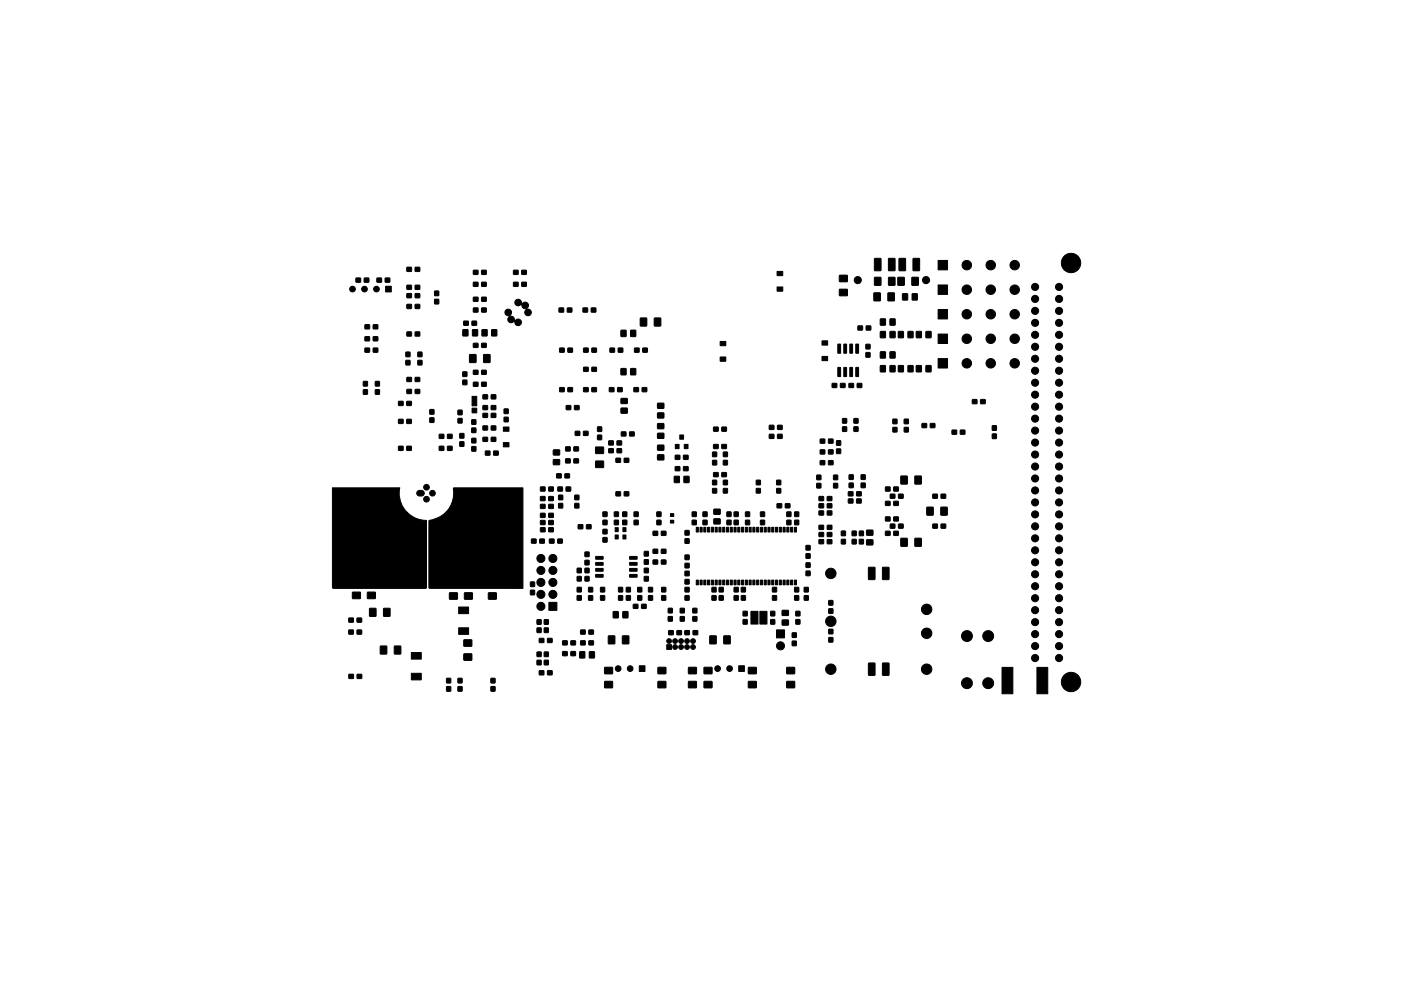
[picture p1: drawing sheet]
<svg xmlns="http://www.w3.org/2000/svg" width="297mm" height="210mm" viewBox="0 0 297 210" stroke-linecap="round" stroke-linejoin="round" font-family="sans-serif">
<g fill="#000" stroke="#000" stroke-width=".21">
<path d="M75.5 59h.9v.9h-.9zM77.2 59h1v.9h-1zM79.9 59h1v.9h-1zM81.7 59h.9v.9h-.9zM86.3 56.7h.9v.9h-.9zM88 56.7h1v.9h-1zM100.4 59.9h.9v.8h-.9zM100.4 57.4h.9v.8h-.9zM102.1 59.9h1v.8h-1zM102.1 57.4h1v.8h-1zM108.9 59.9h.9v.8h-.9zM108.9 57.4h.9v.8h-.9z"/>
<path d="M110.6 59.9h1v.8h-1zM110.6 57.4h1v.8h-1zM164.8 57.6h1.2v.9h-1.2zM178 58.4h1.6l.1 1.3-1.7 .1zM185.4 58.9h1.4l-.1 1.6h-1.3zM185.4 54.9h1.4l-.1 2.5-1.3-.1zM188.4 58.9h1.3v1.6h-1.3zM188.4 54.9h1.4l-.1 2.5-1.3-.1zM190.4 58.9h1.3v1.6h-1.3zM190.6 54.9h1.4l-.1 2.5-1.3-.1zM193.4 58.9h1.3v1.6h-1.4zM193.6 54.9h1.4l-.1 2.5-1.3-.1z"/>
<path d="M198.9 55.3h2v2h-2zM77.4 73.9h.9v.8h-.9zM77.4 71.5h.9v.8h-.9zM77.4 68.9h.9v.9h-.9zM79.1 73.9h1v.8h-1zM79.1 71.5h1v.8h-1zM79.1 68.9h1v.9h-1zM81.8 60.7h1.2v1.2h-1.2zM86.1 76.5h.8v.9h-.8zM86.1 74.7h.8v1h-.8zM86.3 70.4h.9v.9h-.9zM86.3 64.6h.9v.8h-.9z"/>
<path d="M86.3 62.3h.9v.9h-.9zM86.3 60.5h.9v.9h-.9zM88 70.4h1v.9h-1zM88 64.6h1v.8h-1zM88 62.3h1v.9h-1zM88 60.5h1v.9h-1zM88.6 76.5h.9v.9h-.9zM88.6 74.7h.9v1h-.9zM92.2 63.5h.8v1h-.8zM92.2 61.8h.8v.9h-.8zM98.1 78.9h.9v1h-.9zM98.1 70h1.1v1.3l-1.1-.1z"/>
<path d="M98.3 68.2h1v.8h-1zM99.6 75.2l1.3 .1v1.6h-1.3zM100.1 68.2h.9v.8h-.9zM100.2 70h1.1l-.1 1.3-1-.1zM100.4 78.6h.9v.8h-.9zM100.4 72.8h.9v.9h-.9zM100.4 65.4h.9v.8h-.9zM100.4 63.1h.9v.8h-.9zM102.1 78.6h1v.8h-1zM102.1 72.8h1v.9h-1zM102.1 65.4h1v.8h-1zM102.1 63.1h1v.8h-1z"/>
<path d="M102.2 70h1.1l-.1 1.3-1-.1zM102.6 75.2l1.3 .1v1.6h-1.4zM104.3 70h1v1.3l-1.1-.1zM107.3 65.7a.75 .75 0 0 1 1.1 .3 .75 .75 0 0 1-.3 1 .94 .94 0 0 1 1.1 1 .7 .7 0 0 1 1-.2 .7 .7 0 0 1 .1 1.1 .7 .7 0 0 1-1.1-.3l-.1-.5a.78 .78 0 0 1-1.2 .2 .78 .78 0 0 1 .1-1.2v-.1a.77 .77 0 0 1-.8-.4 .77 .77 0 0 1 .1-.9zM109.3 63.7a.81 .81 0 0 1 .9-.1 .81 .81 0 0 1 .4 .8l.1 .1a.77 .77 0 0 1 1.2-.2 .77 .77 0 0 1-.2 1.2 .71 .71 0 0 1 1 .6 .71 .71 0 0 1-.7 .8 .71 .71 0 0 1-.7-.8l.3-.6a.94 .94 0 0 1-1-1 .74 .74 0 0 1-1.1 .3 .74 .74 0 0 1-.2-1.1zM118.5 65.4h1v.8h-1zM118.7 73.9h.9v.8h-.9zM120.3 65.4h.9v.8h-.9zM120.4 73.9h1v.8h-1zM123.6 65.4h1v.8h-1zM123.7 77.9h1v.9h-1zM123.7 73.9h1v.8h-1z"/>
<path d="M125.4 65.4h.9v.8h-.9zM125.5 77.9h.9v.9h-.9zM125.5 73.9h.9v.8h-.9zM129.3 73.9h1v.8h-1zM131.1 73.9h.9v.8h-.9zM131.7 78.2h1v1.3h-1zM131.7 70.1h1v1.3h-1zM133.7 78.2h1.1l-.1 1.3h-1zM133.7 70.1h1.1l-.1 1.3h-1zM134.5 73.9h1v.8h-1zM135.8 67.5h1.3v1.7l-1.3-.1zM136.3 73.9h.9v.8h-.9z"/>
<path d="M138.7 67.5h1.4l-.1 1.7-1.3-.1zM152.7 75.7h1.2v.9h-1.2zM152.7 72.4h1.2v.9h-1.2zM164.8 60.9h1.2v.9h-1.2zM174.3 75.6h1.2v.9h-1.2zM174.3 72.3h1.2v.9h-1.2zM177.7 78h.5v1.9l-.6-.1zM177.7 73l.5 .1v1.8h-.6zM178.9 78h.6l-.1 1.9-.5-.1zM178.9 73l.6 .1-.1 1.8h-.5zM178 61.4h1.6l.1 1.3h-1.7zM180.2 78h.6l-.1 1.9-.5-.1z"/>
<path d="M180.2 73l.6 .1-.1 1.8h-.5zM181.5 78h.5v1.9l-.6-.1zM181.5 73l.5 .1v1.8h-.6zM181.9 69.2h1v.8h-1zM183.6 74.8h.8v1h-.8zM183.6 73.1h.8v.9h-.8zM183.7 69.2h.9v.8h-.9zM185.3 62.2h1.3v1.6h-1.3zM186.7 77.6h1v1.3l-1.1-.1zM186.7 74.7h1v1.3l-1.1-.1zM186.7 70.3l1 .1v1.3l-1.1-.1zM186.7 67.7h1v1.3l-1.1-.1z"/>
<path d="M188.3 62.2h1.3v1.6h-1.3zM188.7 77.6h1.1l-.1 1.3-1-.1zM188.7 74.7h1.1l-.1 1.3-1-.1zM188.7 70.3l1.1 .1-.1 1.3-1-.1zM188.7 67.7h1.1l-.1 1.3-1-.1zM190.5 77.6h1v1.3l-1-.1zM190.5 70.3l1 .1v1.3l-1-.1zM191.4 62.3l1 .1v1.3l-1.1-.1zM192.5 77.6h1.1l-.1 1.3-1-.1zM192.5 70.3l1.1 .1-.1 1.3-1-.1zM193.4 62.3l1.1 .1-.1 1.3-1-.1zM194.3 77.6h1.1l-.1 1.3-1-.1z"/>
<path d="M194.3 70.3l1.1 .1-.1 1.3-1-.1zM196.3 77.6h1.1v1.3l-1.1-.1zM196.3 70.3l1.1 .1v1.3l-1.1-.1zM198.9 76.1h2v2h-2zM198.9 70.9h2v2h-2zM198.9 65.7h2v2h-2zM198.9 60.5h2v2h-2zM77 82.7h.9v.9h-.9zM77 80.9h.9v1h-.9zM79.6 82.7h.8v.9h-.8zM79.6 80.9h.8v1h-.8zM84.5 94.7h1v.8h-1z"/>
<path d="M84.5 89h1v.8h-1zM84.5 85.2h1v.8h-1zM86.3 94.7h.9v.8h-.9zM86.3 89h.9v.8h-.9zM86.3 85.2h.9v.8h-.9zM86.3 82.6h.9v.9h-.9zM86.3 80.1h.9v.8h-.9zM88 82.6h1v.9h-1zM88 80.1h1v.8h-1zM91.1 88.7h.9v.9h-.9zM91.1 86.9h.9v1h-.9zM93.1 94.7h1v.8h-1z"/>
<path d="M93.1 92.2h1v.8h-1zM94.9 94.7h.9v.8h-.9zM94.9 92.2h.9v.8h-.9zM97.1 88.8h.9v.9h-.9zM97.1 87h.9v1h-.9zM97.5 93.7h.8v1h-.8zM97.5 92h.8v.9h-.8zM98.1 80.7h.9v.9h-.9zM100 94.8h.9v.9h-.9zM100 93h.9v1h-.9zM100 90.8h.9v1h-.9zM100 89.1h.9v.9h-.9z"/>
<path d="M100.1 86.6h1v1h-1zM100.1 84.1h1v2h-1zM100.4 81.1h.9v.9h-.9zM102.1 81.1h1v.9h-1zM102.4 92.8h1v.8h-1zM102.4 90.4h1v.8h-1zM102.4 87.7h1v.9h-1zM102.4 86.1h1v.8h-1zM102.4 83.8h1v.8h-1zM102.9 95.7h1v.9h-1zM104.2 92.8h.9v.8h-.9zM104.2 90.4h.9v.8h-.9z"/>
<path d="M104.2 87.7h.9v.9h-.9zM104.2 86.1h.9v.8h-.9zM104.2 83.8h.9v.8h-.9zM104.7 95.7h.9v.9h-.9zM106.9 88.5h.8v1h-.8zM106.9 86.8h.8v.9h-.8zM106.7 93.9h1.2v.9h-1.2zM106.7 90.6h1.2v.9h-1.2zM117.3 97.5h1.3l.1 1-1.3 .1zM117.3 95.5h1.3l.1 1h-1.3zM118.7 82.2h.9v.9h-.9zM119.9 97.4h1v.8h-1z"/>
<path d="M119.9 94.8h1v.9h-1zM120.1 86.1h.9v.8h-.9zM120.4 82.2h1v.9h-1zM121.7 97.4h.9v.8h-.9zM121.7 94.8h.9v.9h-.9zM121.8 86.1h1v.8h-1zM122 91.5h.9v.9h-.9zM123.7 91.5h1v.9h-1zM123.7 82.2h1v.9h-1zM125.5 82.2h.9v.9h-.9zM126.7 92.3h.9v1h-.9zM126.7 90.6h.9v.9h-.9z"/>
<path d="M126.3 97.8h1.6l.1 1.3-1.7 .1zM126.3 94.9h1.6l.1 1.3h-1.7zM129.1 95.2h.9v.8h-.9zM129.1 93.6h.9v.8h-.9zM129.2 82.2h1v.9h-1zM130.6 97.2h1v.9h-1zM130.8 95.2h1v.8h-1zM130.8 93.6h1v.8h-1zM131 82.2h.9v.9h-.9zM131.7 91.6h1v.9h-1zM131.7 86.6h1.3v1l-1.3 .1zM131.7 84.6l1.3-.1v1.1h-1.3z"/>
<path d="M132.4 97.2h.9v.9h-.9zM133.5 91.6h.9v.9h-.9zM134.4 82.2h1v.9h-1zM136.2 82.2h.9v.9h-.9zM139.4 96.5h1.3l.1 1-1.3 .1zM139.4 94.5l1.3-.1 .1 1.1h-1.3zM139.4 91.9h1.3l.1 1.1h-1.3zM139.4 89.9h1.3l.1 1-1.3 .1zM139.4 87.6h1.3l.1 1-1.3 .1zM139.4 85.6l1.3-.1 .1 1.1h-1.3zM143.2 94.3h.8v.9h-.8zM143.2 99h.9v.9h-.9z"/>
<path d="M143.2 96.6h.9v.8h-.9zM144.1 92.3h.8v.9h-.8zM144.9 99h1v.9h-1zM144.9 96.6h1v.8h-1zM145.1 94.3h.8v.9h-.8zM151.1 97.7h.8v.9h-.8zM151.1 95.9h.8v1h-.8zM151.3 94.3h1v.9h-1zM151.3 90.6h1v.9h-1zM153.1 94.3h.9v.9h-.9zM153.1 90.6h.9v.9h-.9zM153.4 97.7h.8v.9h-.8z"/>
<path d="M153.4 95.9h.8v1h-.8zM163.1 92.2h1v.8h-1zM163.1 90.2h1v.9h-1zM164.9 92.2h.9v.8h-.9zM164.9 90.2h.9v.9h-.9zM173.9 97.7h1v.9h-1zM173.9 95.5h1v.8h-1zM173.9 93.2h1v.8h-1zM175.7 97.7h.9v.9h-.9zM175.7 95.5h.9v.8h-.9zM175.7 93.2h.9v.8h-.9zM176.5 81.4h.9v.8h-.9z"/>
<path d="M177.4 95.3h.8v.9h-.8zM177.4 93.5h.8v1h-.8zM178.2 81.4h.9v.8h-.9zM178.6 90.6h.9v.9h-.9zM178.6 88.8h.9v1h-.9zM180 81.4h1v.8h-1zM181.1 90.6h.8v.9h-.8zM181.1 88.8h.8v1h-.8zM181.8 81.4h.9v.8h-.9zM189.3 90.7h.9v.9h-.9zM189.3 88.9h.9v1h-.9zM191.7 90.7h.9v.9h-.9z"/>
<path d="M191.7 88.9h.9v1h-.9zM195.5 89.9h.9v.8h-.9zM197.3 89.9h.9v.8h-.9zM201.9 91.3h.9v.8h-.9zM203.6 91.3h1v.8h-1zM206.2 84.8h.9v.8h-.9zM207.9 84.8h1v.8h-1zM210.4 92.1h.8v.9h-.8zM210.4 90.3h.8v1h-.8zM70.5 103.5h14.3l-.2 1.6 .3 1.3 .4 .9 .6 1 1.1 1a5.4 5.4 0 0 0 2.7 1.1h.7v14.3l-.1 .1h-19.7l-.1-.1zM88.5 104.2l.9-.2a.6 .6 0 0 1 .6 .6 .6 .6 0 0 1-.6 .6h-.5a.6 .6 0 0 1-.5-.3 .6 .6 0 0 1 .1-.7zM112.7 114.4h.9v.8h-.9z"/>
<path d="M114.4 114.4h1v.8h-1zM114.6 112h.9v.8h-.9zM114.6 110.4h.9v.9h-.9zM114.6 108.9h.9v.9h-.9zM114.6 107h.9v.9h-.9zM114.6 105.4h.9v.8h-.9zM114.6 103.3h.9v.9h-.9zM116.4 112h.9v.8h-.9zM116.4 110.4h.9v.9h-.9zM116.4 108.9h.9v.9h-.9zM116.4 107h.9v.9h-.9zM116.4 105.4h.9v.8h-.9z"/>
<path d="M116.4 103.3h.9v.9h-.9zM116.5 114.4h1v.8h-1zM118 100.5h1v.9h-1zM118.3 114.4h.9v.8h-.9zM118.3 103.3h.9v.9h-.9zM118.4 106.8h.9v1h-.9zM118.4 105.1h.9v.9h-.9zM119.8 100.5h.9v.9h-.9zM120 103.3h1v.9h-1zM121.9 106.8h.8v1h-.8zM121.9 105.1h.8v.9h-.8zM122.6 111.3h1v.9h-1z"/>
<path d="M124 118.9h.9v.9h-.9zM124 117.1h.9v1h-.9zM124.4 111.3h.9v.9h-.9zM126.3 119.4l1.5-.1 .1 .6h-1.6zM126.3 118.1h1.5l.1 .5-1.6 .1zM127.8 114.1h.9v.9h-.9zM127.8 112.3h.9v1h-.9zM127.8 110.4h.9v.9h-.9zM127.8 108.6h.9v1h-.9zM130.3 110.4h.8v.9h-.8zM130.3 108.6h.8v1h-.8zM130.4 113.5h.7v.9h-.7z"/>
<path d="M130.4 112h.7v.8h-.7zM130.6 104.3h1v.9h-1zM132.1 113.5h.6v.9h-.6zM132.1 112h.6v.8h-.6zM132 110.4h.9v.9h-.9zM132 108.6h.9v1h-.9zM132.4 104.3h.9v.9h-.9zM133.5 119.4l1.5-.1 .1 .6h-1.6zM133.5 118.1h1.5l.1 .5-1.6 .1zM134.5 110.4h.8v.9h-.8zM134.5 108.6h.8v1h-.8zM136.6 118.8h.9v.9h-.9z"/>
<path d="M136.6 117h.9v1h-.9zM138.5 118.8h.9v.9h-.9zM138.5 116.5h.9v.9h-.9zM138.5 112.7h.9v.9h-.9zM139.3 110.4h.8v.9h-.8zM139.3 108.6h.8v1h-.8zM140.2 118.8h1v.9h-1zM140.2 116.5h1v.9h-1zM140.2 112.7h1v.9h-1zM142.1 110.4h.7v.6h-.7zM142.1 109h.7v.6h-.7zM143 101.1h1v1.3l-1-.1z"/>
<path d="M145 101.1h1.1l-.1 1.3-1-.1zM145.2 119.5h.9v1h-.9zM145.2 117.8h.9v.9h-.9zM145.2 114.3h.9v1h-.9zM145.2 112.6h.9v.9h-.9zM146.8 110.4h.8v.9h-.8zM146.8 108.6h.8v1h-.8zM147.6 111.9h.5v1h-.5zM148.4 111.9h.5v1h-.5zM149.2 111.9h.5v1h-.5zM149.1 110.4h.8v.9h-.8zM149.1 108.6h.8v1h-.8z"/>
<path d="M150 111.9h.5v1h-.5zM150.8 111.9h.5v1h-.5zM151.1 103.6h.8v1h-.8zM151.1 101.9h.8v.9h-.8zM151.6 111.9h.5v1h-.5zM151.3 100.3h1v.8h-1zM151.4 110.1h1.2l.1 1-1.3 .1zM151.4 108h1.2l.1 1.1h-1.3zM152.4 111.9h.5v1h-.5zM153.2 111.9h.5v1h-.5zM153.1 100.3h.9v.8h-.9zM153.4 103.6h.8v1h-.8z"/>
<path d="M153.4 101.9h.8v.9h-.8zM154 111.9h.5v1h-.5zM154.1 110.4h.9v.9h-.9zM154.1 108.6h.9v1h-.9zM154.8 111.9h.5v1h-.5zM155.6 111.9h.5v1h-.5zM155.7 110.4h.8v.9h-.8zM155.7 108.6h.8v1h-.8zM156.4 111.9h.5v1h-.5zM157.2 111.9h.5v1h-.5zM158 111.9h.5v1h-.5zM158.1 110.4h.8v.9h-.8z"/>
<path d="M158.1 108.6h.8v1h-.8zM158.8 111.9h.5v1h-.5zM159.6 111.9h.5v1h-.5zM160.4 111.9h.5v1h-.5zM160.4 103.6h.8v1h-.8zM160.4 101.9h.8v.9h-.8zM161.2 111.9h.5v1h-.5zM161.2 110.4h.9v.9h-.9zM161.2 108.6h.9v1h-.9zM162 111.9h.5v1h-.5zM162.8 111.9h.5v1h-.5zM163.6 111.9h.5v1h-.5z"/>
<path d="M164.4 111.9h.5v1h-.5zM164.7 103.6h.8v1h-.8zM164.7 101.9h.8v.9h-.8zM164.8 106.9h.9v.8h-.9zM165.2 111.9h.5v1h-.5zM166 111.9h.5v1h-.5zM166.8 111.9h.5v1h-.5zM166.5 106.9h1v.8h-1zM166.8 110.4h.9v.9h-.9zM166.8 108.6h.9v1h-.9zM167.6 111.9h.5v1h-.5zM168.4 111.9h.5v1h-.5z"/>
<path d="M168.5 110.4h.8v.9h-.8zM168.5 108.6h.8v1h-.8zM170.9 119.4h.8v1h-.8zM170.9 117.5h.8v.9h-.8zM170.9 115.7h.8v1h-.8zM173.2 102.6h.8v.9h-.8zM173.2 100.8h.8v1h-.8zM173.7 114.5h.9v.9h-.9zM173.7 113h.9v.8h-.9zM173.7 111.5h.9v.8h-.9zM173.7 108.4h.9v.9h-.9zM173.7 106.9h.9v.8h-.9z"/>
<path d="M173.7 105.4h.9v.8h-.9zM175.4 114.5h1v.9h-1zM175.4 113h1v.8h-1zM175.4 111.5h1v.8h-1zM175.4 108.4h1v.9h-1zM175.4 106.9h1v.8h-1zM175.4 105.4h1v.8h-1zM176.7 102.6h.9v.9h-.9zM176.7 100.8h.9v1h-.9zM178.4 114.4h.8v1h-.8zM178.4 112.7h.8v.9h-.8zM179.9 105.9h.9v.8h-.9z"/>
<path d="M179.9 104.3h.9v.9h-.9zM180 102.5h.9v1h-.9zM180 100.8h.9v.9h-.9zM180.7 114.4h.8v1h-.8zM180.7 112.7h.8v.9h-.8zM181.6 105.9h1v.8h-1zM181.6 104.3h1v.9h-1zM182.2 114.4h.8v1h-.8zM182.2 112.7h.8v.9h-.8zM182.6 102.5h.8v1h-.8zM182.6 100.8h.8v.9h-.8zM183.8 114.5h1.2l.1 1.1h-1.3z"/>
<path d="M183.8 112.5h1.2l.1 1-1.3 .1zM187.8 112.7h.9v.9h-.9zM187.8 109.7h.9v.8h-.9zM187.8 106.4h.9v.8h-.9zM187.8 103.3h.9v.9h-.9zM188.8 111.2h.9v.9h-.9zM188.8 104.9h.9v.8h-.9zM189.5 112.7h1v.9h-1zM189.5 109.7h1v.8h-1zM189.5 106.4h1v.8h-1zM189.5 103.3h1v.9h-1zM190.5 111.2h1v.9h-1z"/>
<path d="M190.5 104.9h1v.8h-1zM191 114.2l1.4 .1-.1 1.6h-1.3zM191 101h1.4l-.1 1.7-1.3-.1zM194 114.2l1.3 .1v1.6h-1.3zM194 101h1.3v1.7l-1.3-.1zM196.5 107.6l1.4 .1-.1 1.6h-1.3zM197.8 111.2h.9v.9h-.9zM197.8 104.9h.9v.8h-.9zM199.5 111.2h1v.9h-1zM199.5 104.9h1v.8h-1zM199.5 107.6l1.3 .1v1.6h-1.3zM74 133.7h.9v.8h-.9z"/>
<path d="M74 131.1h.9v.9h-.9zM74.7 125.7l1.7-.1v1.4h-1.6zM75.7 133.7h1v.8h-1zM75.7 131.1h1v.9h-1zM77.9 125.7l1.6-.1 .1 1.4h-1.7zM78.4 129.1h1.3v1.7l-1.4-.1zM80.7 137.1h1.3v1.7l-1.4-.1zM81.3 129.1h1.4l-.1 1.7-1.3-.1zM83.6 137.1h1.4l-.1 1.7-1.3-.1zM87.2 138.4h2.1v1.4h-2.1zM95.3 125.8h1.6l.1 1.3h-1.7zM97.2 133.2h2.1v1.4h-2.1z"/>
<path d="M97.2 128.8h2.1v1.4h-2.1zM98.4 138.7h1.6v1.3l-1.6 .1zM98.4 135.8l1.6-.1v1.4h-1.6zM98.5 125.8h1.6l.1 1.3h-1.7zM103.6 125.8h1.6v1.3h-1.6zM96.2 103.5h14.7v21.3h-19.8l-.2-.1v-14.2l.9-.3a6.1 6.1 0 0 0 3.1-1.9l.7-1.2 .4-1.1zM112.5 125.2h.8v1h-.8zM112.5 123.5h.8v.9h-.8zM113.9 138.3h.8v1h-.8zM113.9 133.2h.8v1h-.8zM113.9 131.5h.8v.9h-.8zM114.3 135.5h1v.8h-1z"/>
<path d="M115.4 138.3h.8v1h-.8zM115.4 133.2h.8v1h-.8zM115.4 131.5h.8v.9h-.8zM116.1 135.5h.9v.8h-.9zM116.4 127.8h1.7v1.7h-1.7zM119.3 138.3h.9v.8h-.9zM119.3 136h.9v.8h-.9zM121.1 138.3h.9v.8h-.9zM121.1 136h.9v.8h-.9zM122.4 126.4h.8v.9h-.8zM122.4 124.6h.8v1h-.8zM122.4 122.3h.8v1h-.8z"/>
<path d="M122.4 120.6h.8v.9h-.8zM122.9 138.3h1.1l-.1 1.3h-1zM123.1 136h1v.8h-1zM123.1 133.7h1v.8h-1zM124 122.3h.9v1h-.9zM124 120.6h.9v.9h-.9zM124.8 126.4h.8v.9h-.8zM124.8 124.6h.8v1h-.8zM124.9 136h.9v.8h-.9zM124.9 133.7h.9v.8h-.9zM125 138.3h1v1.3h-1.1zM126.3 121.9h1.5l.1 .5-1.6 .1z"/>
<path d="M126.3 120.6h1.5l.1 .5-1.6 .1zM127.3 126.4h.9v.9h-.9zM127.3 124.6h.9v1h-.9zM129 134.9l1.4 .1-.1 1.6h-1.3zM130 129.8h1.1l-.1 1.3-1-.1zM131.1 126.4h.9v.9h-.9zM131.1 124.6h.9v1h-.9zM132.1 129.8h1v1.3l-1-.1zM132 134.9l1.3 .1v1.6h-1.3zM132.8 126.4h.8v.9h-.8zM132.8 124.6h.8v1h-.8zM133.5 121.9h1.5l.1 .5-1.6 .1z"/>
<path d="M133.5 120.6h1.5l.1 .5-1.6 .1zM134.3 128.2h.9v.9h-.9zM135.2 126.4h.9v.9h-.9zM135.2 124.6h.9v1h-.9zM136 128.2h1v.9h-1zM136.6 122.3h.9v1h-.9zM136.6 120.6h.9v.9h-.9zM137.5 126.4h.8v.9h-.8zM137.5 124.6h.8v1h-.8zM140.3 126.4h.8v.9h-.8zM140.3 124.6h.8v1h-.8zM141.4 136.8h1v1h-1z"/>
<path d="M141.7 130.8h.8v1h-.8zM141.7 129.1h.8v.9h-.8zM141.8 133.8h.9v.9h-.9zM143.5 133.8h1v.9h-1zM144.2 130.8h.9v1h-.9zM144.2 129.1h.9v.9h-.9zM145.2 126.4h.9v.9h-.9zM145.2 124.6h.9v1h-.9zM145.2 123h.9v.9h-.9zM145.2 121.2h.9v.9h-.9zM145.2 133.8h1v.9h-1zM146.9 130.8h.8v1h-.8z"/>
<path d="M146.9 129.1h.8v.9h-.8zM147 133.8h.9v.9h-.9zM147.6 123.1h.5v1h-.5zM148.4 123.1h.5v1h-.5zM149.2 123.1h.5v1h-.5zM150 123.1h.5v1h-.5zM150.8 123.1h.5v1h-.5zM151 126.4h.8v.9h-.8zM151 124.6h.8v1h-.8zM150.5 134.9l1.4 .1-.1 1.6h-1.3zM151.6 123.1h.5v1h-.5zM152.4 123.1h.5v1h-.5z"/>
<path d="M152.5 126.4h.8v.9h-.8zM152.5 124.6h.8v1h-.8zM153.2 123.1h.5v1h-.5zM154 123.1h.5v1h-.5zM153.5 134.9l1.3 .1v1.6h-1.3zM154.8 123.1h.5v1h-.5zM155.6 123.1h.5v1h-.5zM155.7 126.4h.8v.9h-.8zM155.7 124.6h.8v1h-.8zM156.4 123.1h.5v1h-.5zM157.2 123.1h.5v1h-.5zM157.2 126.4h.8v.9h-.8z"/>
<path d="M157.2 124.6h.8v1h-.8zM157.6 131.5h.8v.9h-.8zM157.6 129.7h.8v1h-.8zM158 123.1h.5v1h-.5zM158.8 123.1h.5v1h-.5zM159.6 123.1h.5v1h-.5zM159.2 129.7h1.5v2.7h-1.5zM160.4 123.1h.5v1h-.5zM161.2 123.1h.5v1h-.5zM162 123.1h.5v1h-.5zM161.1 129.7h1.5v2.7h-1.5zM162.8 123.1h.5v1h-.5z"/>
<path d="M163.6 123.1h.5v1h-.5zM163.4 131.5h.9v.9h-.9zM163.4 129.7h.9v1h-.9zM163.8 126.4h.8v.9h-.8zM163.8 124.6h.8v1h-.8zM164.4 123.1h.5v1h-.5zM165.2 123.1h.5v1h-.5zM164.6 133.6h1.7v1.7h-1.7zM166 123.1h.5v1h-.5zM165.9 131.6l1.2-.1 .1 1.1h-1.3zM165.9 129.5h1.2l.1 1-1.3 .1zM166.8 123.1h.5v1h-.5z"/>
<path d="M167.6 123.1h.5v1h-.5zM168 136h.8v1h-.8zM168 134.3h.8v.9h-.8zM168.4 123.1h.5v1h-.5zM168.5 126.4h.8v.9h-.8zM168.5 124.6h.8v1h-.8zM168.7 131.5h.9v.9h-.9zM168.7 129.7h.9v1h-.9zM170.5 126.4h.9v.9h-.9zM170.5 124.6h.9v1h-.9zM170.9 121.2h.8v.9h-.8zM175.7 135.3h.9v.9h-.9z"/>
<path d="M175.7 133.5h.9v1h-.9zM175.7 129.2h.9v.9h-.9zM175.7 127.4h.9v1h-.9zM184.2 120.4h1.3l-.1 2.6-1.3-.1zM187.1 120.4h1.4l-.1 2.6-1.3-.1zM74 143.1h.9v.8h-.9zM75.7 143.1h1v.8h-1zM87.2 142.8h2.1v1.4h-2.1zM94.7 145.7h.8v.9h-.8zM94.7 143.9h.8v1h-.8zM97.1 145.7h.9v.9h-.9zM97.1 143.9h.9v1h-.9z"/>
<path d="M104.1 145.7h.8v.9h-.8zM104.1 143.9h.8v1h-.8zM113.9 140.1h.8v.9h-.8zM114.3 142.3h1v.9h-1zM115.4 140.1h.8v.9h-.8zM116.1 142.3h.9v.9h-.9zM128.2 144.6h1.6l.1 1.3h-1.7zM128.2 141.6h1.6l.1 1.3-1.7 .1zM135.5 141.3h1.2v1.2h-1.2zM139.5 144.6h1.6l.1 1.3h-1.7zM139.5 141.6h1.6l.1 1.3-1.7 .1zM146 144.6h1.6l.1 1.3h-1.7z"/>
<path d="M146 141.6h1.6l.1 1.3-1.7 .1zM149.3 144.6h1.6l.1 1.3h-1.7zM149.3 141.6h1.6l.1 1.3-1.7 .1zM156.6 141.3h1.2v1.2h-1.2zM158.7 144.6h1.6l.1 1.3h-1.7zM158.7 141.6h1.6l.1 1.3-1.7 .1zM166.8 144.6h1.6l.1 1.3h-1.7zM166.8 141.6h1.6l.1 1.3-1.7 .1zM184.2 140.7l1.3 .1-.1 2.5-1.3-.1zM187.1 140.7l1.4 .1-.1 2.5-1.3-.1zM212.4 141.6h2.3v5.6h-2.3zM219.8 141.6h2.3v5.6h-2.3z"/>
<circle cx="181.9" cy="59.4" r=".75"/>
<circle cx="196.3" cy="59.4" r=".75"/>
<circle cx="205" cy="56.3" r="1"/>
<circle cx="210.1" cy="56.3" r="1"/>
<circle cx="215.1" cy="56.3" r="1"/>
<circle cx="227.1" cy="55.8" r="2.06"/>
<circle cx="74.7" cy="61.3" r=".6"/>
<circle cx="77.3" cy="61.3" r=".6"/>
<circle cx="79.8" cy="61.3" r=".6"/>
<circle cx="205" cy="66.7" r="1"/>
<circle cx="205" cy="61.5" r="1"/>
<circle cx="205" cy="71.9" r="1"/>
<circle cx="205" cy="77.1" r="1"/>
<circle cx="210.1" cy="66.7" r="1"/>
<circle cx="210.1" cy="61.5" r="1"/>
<circle cx="210.1" cy="77.1" r="1"/>
<circle cx="210.1" cy="71.9" r="1"/>
<circle cx="215.1" cy="66.7" r="1"/>
<circle cx="215.1" cy="61.5" r="1"/>
<circle cx="215.1" cy="71.9" r="1"/>
<circle cx="215.1" cy="77.1" r="1"/>
<circle cx="219.5" cy="78.7" r=".75"/>
<circle cx="219.5" cy="63.4" r=".75"/>
<circle cx="219.5" cy="73.6" r=".75"/>
<circle cx="219.5" cy="68.5" r=".75"/>
<circle cx="219.5" cy="66" r=".75"/>
<circle cx="219.5" cy="71" r=".75"/>
<circle cx="219.5" cy="60.9" r=".75"/>
<circle cx="219.5" cy="76.1" r=".75"/>
<circle cx="224.5" cy="78.7" r=".75"/>
<circle cx="224.5" cy="73.6" r=".75"/>
<circle cx="224.5" cy="68.5" r=".75"/>
<circle cx="224.5" cy="66" r=".75"/>
<circle cx="224.5" cy="63.4" r=".75"/>
<circle cx="224.5" cy="71" r=".75"/>
<circle cx="224.5" cy="76.1" r=".75"/>
<circle cx="224.5" cy="60.9" r=".75"/>
<circle cx="219.5" cy="81.2" r=".75"/>
<circle cx="219.5" cy="99" r=".75"/>
<circle cx="219.5" cy="96.4" r=".75"/>
<circle cx="219.5" cy="93.9" r=".75"/>
<circle cx="219.5" cy="91.4" r=".75"/>
<circle cx="219.5" cy="86.3" r=".75"/>
<circle cx="219.5" cy="83.7" r=".75"/>
<circle cx="219.5" cy="88.8" r=".75"/>
<circle cx="224.5" cy="99" r=".75"/>
<circle cx="224.5" cy="81.2" r=".75"/>
<circle cx="224.5" cy="93.9" r=".75"/>
<circle cx="224.5" cy="91.4" r=".75"/>
<circle cx="224.5" cy="83.7" r=".75"/>
<circle cx="224.5" cy="96.4" r=".75"/>
<circle cx="224.5" cy="86.3" r=".75"/>
<circle cx="224.5" cy="88.8" r=".75"/>
<circle cx="90.4" cy="105.9" r=".6"/>
<circle cx="90.4" cy="103.4" r=".6"/>
<circle cx="91.7" cy="104.6" r=".6"/>
<circle cx="114.7" cy="118.5" r=".85"/>
<circle cx="117.2" cy="118.5" r=".85"/>
<circle cx="219.5" cy="119.3" r=".75"/>
<circle cx="219.5" cy="114.2" r=".75"/>
<circle cx="219.5" cy="111.7" r=".75"/>
<circle cx="219.5" cy="109.1" r=".75"/>
<circle cx="219.5" cy="106.6" r=".75"/>
<circle cx="219.5" cy="104.1" r=".75"/>
<circle cx="219.5" cy="101.5" r=".75"/>
<circle cx="219.5" cy="116.8" r=".75"/>
<circle cx="224.5" cy="119.3" r=".75"/>
<circle cx="224.5" cy="114.2" r=".75"/>
<circle cx="224.5" cy="104.1" r=".75"/>
<circle cx="224.5" cy="111.7" r=".75"/>
<circle cx="224.5" cy="109.1" r=".75"/>
<circle cx="224.5" cy="101.5" r=".75"/>
<circle cx="224.5" cy="106.6" r=".75"/>
<circle cx="224.5" cy="116.8" r=".75"/>
<circle cx="114.7" cy="123.6" r=".85"/>
<circle cx="114.7" cy="121" r=".85"/>
<circle cx="114.7" cy="126.1" r=".85"/>
<circle cx="114.7" cy="128.6" r=".85"/>
<circle cx="117.2" cy="121" r=".85"/>
<circle cx="117.2" cy="126.1" r=".85"/>
<circle cx="117.2" cy="123.6" r=".85"/>
<circle cx="141.9" cy="136" r=".5"/>
<circle cx="143.1" cy="137.3" r=".5"/>
<circle cx="143.1" cy="136" r=".5"/>
<circle cx="144.4" cy="137.3" r=".5"/>
<circle cx="144.4" cy="136" r=".5"/>
<circle cx="145.7" cy="137.3" r=".5"/>
<circle cx="145.7" cy="136" r=".5"/>
<circle cx="146.9" cy="137.3" r=".5"/>
<circle cx="146.9" cy="136" r=".5"/>
<circle cx="165.5" cy="137" r=".85"/>
<circle cx="176.1" cy="131.8" r="1.11"/>
<circle cx="176.1" cy="121.7" r="1.11"/>
<circle cx="196.5" cy="129.3" r="1.11"/>
<circle cx="196.5" cy="134.4" r="1.1"/>
<circle cx="205" cy="135" r="1.15"/>
<circle cx="209.5" cy="135" r="1.15"/>
<circle cx="219.5" cy="124.4" r=".75"/>
<circle cx="219.5" cy="121.8" r=".75"/>
<circle cx="219.5" cy="139.6" r=".75"/>
<circle cx="219.5" cy="137.1" r=".75"/>
<circle cx="219.5" cy="129.5" r=".75"/>
<circle cx="219.5" cy="132" r=".75"/>
<circle cx="219.5" cy="126.9" r=".75"/>
<circle cx="219.5" cy="134.5" r=".75"/>
<circle cx="224.5" cy="124.4" r=".75"/>
<circle cx="224.5" cy="121.8" r=".75"/>
<circle cx="224.5" cy="139.6" r=".75"/>
<circle cx="224.5" cy="137.1" r=".75"/>
<circle cx="224.5" cy="132" r=".75"/>
<circle cx="224.5" cy="129.5" r=".75"/>
<circle cx="224.5" cy="126.9" r=".75"/>
<circle cx="224.5" cy="134.5" r=".75"/>
<circle cx="131.1" cy="141.9" r=".6"/>
<circle cx="133.6" cy="141.9" r=".6"/>
<circle cx="152.1" cy="141.9" r=".6"/>
<circle cx="154.7" cy="141.9" r=".6"/>
<circle cx="176.1" cy="142" r="1.11"/>
<circle cx="196.5" cy="142" r="1.11"/>
<circle cx="205" cy="145" r="1.15"/>
<circle cx="209.5" cy="145" r="1.15"/>
<circle cx="227.1" cy="144.7" r="2.05"/>
</g>
</svg>
